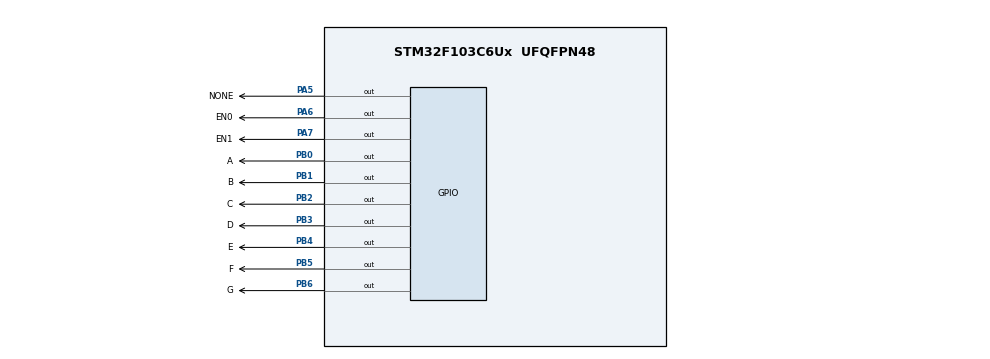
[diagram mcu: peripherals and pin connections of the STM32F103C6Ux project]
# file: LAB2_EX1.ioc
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Mcu.Family=STM32F1
Mcu.Name=STM32F103C6Ux
Mcu.Package=UFQFPN48
NVIC.PriorityGroup=NVIC_PRIORITYGROUP_4
NVIC.TIM2_IRQn=true\:0\:0\:false\:false\:true\:true\:true
PA5.GPIO_Label=NONE
PA5.Signal=GPIO_Output
PA6.GPIO_Label=EN0
PA6.Signal=GPIO_Output
PA7.GPIO_Label=EN1
PA7.Signal=GPIO_Output
PB0.GPIO_Label=A
PB0.Signal=GPIO_Output
PB1.GPIO_Label=B
PB1.Signal=GPIO_Output
PB2.GPIO_Label=C
PB2.Signal=GPIO_Output
PB3.GPIO_Label=D
PB3.Signal=GPIO_Output
PB4.GPIO_Label=E
PB4.Signal=GPIO_Output
PB5.GPIO_Label=F
PB5.Signal=GPIO_Output
PB6.GPIO_Label=G
PB6.Signal=GPIO_Output
ProjectManager.HeapSize=0x200
ProjectManager.StackSize=0x400
ProjectManager.TargetToolchain=STM32CubeIDE
RCC.APB1Freq_Value=8000000
RCC.APB2Freq_Value=8000000
TIM2.Period=9
TIM2.Prescaler=7999
VP_SYS_VS_ND.Mode=No_Debug
VP_TIM2_VS_ClockSourceINT.Mode=Internal
board=custom

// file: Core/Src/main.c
/* USER CODE BEGIN Header */
/**
  ******************************************************************************
  * @file           : main.c
  * @brief          : Main program body
  ******************************************************************************
  * @attention
  *
  * <h2><center>&copy; Copyright (c) 2025 STMicroelectronics.
  * All rights reserved.</center></h2>
  *
  * This software component is licensed by ST under BSD 3-Clause license,
  * the "License"; You may not use this file except in compliance with the
  * License. You may obtain a copy of the License at:
  *                        opensource.org/licenses/BSD-3-Clause
  *
  ******************************************************************************
  */
/* USER CODE END Header */
#include "main.h"

TIM_HandleTypeDef htim2;
int timer2_counter = 50;
int status = 0;

void SystemClock_Config(void);
static void MX_TIM2_Init(void);
static void MX_GPIO_Init(void);

/* USER CODE BEGIN 0 */

void setTimer2(int duration) {
    timer2_counter = duration;
}

void display7SEG(int num) {
    switch (num) {
        case 0:
            HAL_GPIO_WritePin(GPIOB, NUM0_Pin|NUM1_Pin|NUM2_Pin|NUM3_Pin|NUM4_Pin|NUM5_Pin, GPIO_PIN_RESET);
            HAL_GPIO_WritePin(GPIOB, NUM6_Pin, GPIO_PIN_SET);
            break;
        case 1:
            HAL_GPIO_WritePin(GPIOB, NUM0_Pin, GPIO_PIN_SET);
            HAL_GPIO_WritePin(GPIOB, NUM1_Pin|NUM2_Pin, GPIO_PIN_RESET);
            HAL_GPIO_WritePin(GPIOB, NUM3_Pin|NUM4_Pin|NUM5_Pin|NUM6_Pin, GPIO_PIN_SET);
            break;
        case 2:
            HAL_GPIO_WritePin(GPIOB, NUM0_Pin|NUM1_Pin|NUM3_Pin|NUM4_Pin|NUM6_Pin, GPIO_PIN_RESET);
            HAL_GPIO_WritePin(GPIOB, NUM2_Pin|NUM5_Pin, GPIO_PIN_SET);
            break;
        case 3:
            HAL_GPIO_WritePin(GPIOB, NUM0_Pin|NUM1_Pin|NUM2_Pin|NUM3_Pin|NUM6_Pin, GPIO_PIN_RESET);
            HAL_GPIO_WritePin(GPIOB, NUM4_Pin|NUM5_Pin, GPIO_PIN_SET);
            break;
        case 4:
            HAL_GPIO_WritePin(GPIOB, NUM1_Pin|NUM2_Pin|NUM5_Pin|NUM6_Pin, GPIO_PIN_RESET);
            HAL_GPIO_WritePin(GPIOB, NUM0_Pin|NUM3_Pin|NUM4_Pin, GPIO_PIN_SET);
            break;
        case 5:
            HAL_GPIO_WritePin(GPIOB, NUM0_Pin|NUM2_Pin|NUM3_Pin|NUM5_Pin|NUM6_Pin, GPIO_PIN_RESET);
            HAL_GPIO_WritePin(GPIOB, NUM1_Pin|NUM4_Pin, GPIO_PIN_SET);
            break;
        case 6:
            HAL_GPIO_WritePin(GPIOB, NUM0_Pin|NUM2_Pin|NUM3_Pin|NUM4_Pin|NUM5_Pin|NUM6_Pin, GPIO_PIN_RESET);
            HAL_GPIO_WritePin(GPIOB, NUM1_Pin, GPIO_PIN_SET);
            break;
        case 7:
            HAL_GPIO_WritePin(GPIOB, NUM0_Pin|NUM1_Pin|NUM2_Pin, GPIO_PIN_RESET);
            HAL_GPIO_WritePin(GPIOB, NUM3_Pin|NUM4_Pin|NUM5_Pin|NUM6_Pin, GPIO_PIN_SET);
            break;
        case 8:
            HAL_GPIO_WritePin(GPIOB, NUM0_Pin|NUM1_Pin|NUM2_Pin|NUM3_Pin|NUM4_Pin|NUM5_Pin|NUM6_Pin, GPIO_PIN_RESET);
            break;
        case 9:
            HAL_GPIO_WritePin(GPIOB, NUM0_Pin|NUM1_Pin|NUM2_Pin|NUM3_Pin|NUM5_Pin|NUM6_Pin, GPIO_PIN_RESET);
            HAL_GPIO_WritePin(GPIOB, NUM4_Pin, GPIO_PIN_SET);
            break;
        default:
            break;
    }
}
/* USER CODE END 0 */

int main(void)
{

  /* MCU Configuration--------------------------------------------------------*/

  /* Reset of all peripherals, Initializes the Flash interface and the Systick. */
  HAL_Init();

  /* Configure the system clock */
  SystemClock_Config();

  /* Initialize all configured peripherals */
  MX_TIM2_Init();
  MX_GPIO_Init();
  /* USER CODE BEGIN 2 */
  HAL_TIM_Base_Start_IT(&htim2 );
  setTimer2(50);
  /* USER CODE END 2 */

  /* Infinite loop */
  while (1)
  {

  }
}

void SystemClock_Config(void)
{
  RCC_OscInitTypeDef RCC_OscInitStruct = {0};
  RCC_ClkInitTypeDef RCC_ClkInitStruct = {0};

  /** Initializes the RCC Oscillators according to the specified parameters
  * in the RCC_OscInitTypeDef structure.
  */
  RCC_OscInitStruct.OscillatorType = RCC_OSCILLATORTYPE_HSI;
  RCC_OscInitStruct.HSIState = RCC_HSI_ON;
  RCC_OscInitStruct.HSICalibrationValue = RCC_HSICALIBRATION_DEFAULT;
  RCC_OscInitStruct.PLL.PLLState = RCC_PLL_NONE;
  if (HAL_RCC_OscConfig(&RCC_OscInitStruct) != HAL_OK)
  {
    Error_Handler();
  }
  /** Initializes the CPU, AHB and APB buses clocks
  */
  RCC_ClkInitStruct.ClockType = RCC_CLOCKTYPE_HCLK|RCC_CLOCKTYPE_SYSCLK
                              |RCC_CLOCKTYPE_PCLK1|RCC_CLOCKTYPE_PCLK2;
  RCC_ClkInitStruct.SYSCLKSource = RCC_SYSCLKSOURCE_HSI;
  RCC_ClkInitStruct.AHBCLKDivider = RCC_SYSCLK_DIV1;
  RCC_ClkInitStruct.APB1CLKDivider = RCC_HCLK_DIV1;
  RCC_ClkInitStruct.APB2CLKDivider = RCC_HCLK_DIV1;

  if (HAL_RCC_ClockConfig(&RCC_ClkInitStruct, FLASH_LATENCY_0) != HAL_OK)
  {
    Error_Handler();
  }
}

static void MX_TIM2_Init(void)
{

  TIM_ClockConfigTypeDef sClockSourceConfig = {0};
  TIM_MasterConfigTypeDef sMasterConfig = {0};

  htim2.Instance = TIM2;
  htim2.Init.Prescaler = 7999;
  htim2.Init.CounterMode = TIM_COUNTERMODE_UP;
  htim2.Init.Period = 9;
  htim2.Init.ClockDivision = TIM_CLOCKDIVISION_DIV1;
  htim2.Init.AutoReloadPreload = TIM_AUTORELOAD_PRELOAD_DISABLE;
  if (HAL_TIM_Base_Init(&htim2) != HAL_OK)
  {
    Error_Handler();
  }
  sClockSourceConfig.ClockSource = TIM_CLOCKSOURCE_INTERNAL;
  if (HAL_TIM_ConfigClockSource(&htim2, &sClockSourceConfig) != HAL_OK)
  {
    Error_Handler();
  }
  sMasterConfig.MasterOutputTrigger = TIM_TRGO_RESET;
  sMasterConfig.MasterSlaveMode = TIM_MASTERSLAVEMODE_DISABLE;
  if (HAL_TIMEx_MasterConfigSynchronization(&htim2, &sMasterConfig) != HAL_OK)
  {
    Error_Handler();
  }

}

static void MX_GPIO_Init(void)
{
  GPIO_InitTypeDef GPIO_InitStruct = {0};

  /* GPIO Ports Clock Enable */
  __HAL_RCC_GPIOA_CLK_ENABLE();
  __HAL_RCC_GPIOB_CLK_ENABLE();

  /*Configure GPIO pin Output Level */
  HAL_GPIO_WritePin(GPIOA, NONE_Pin|EN0_Pin|EN1_Pin, GPIO_PIN_RESET);

  /*Configure GPIO pin Output Level */
  HAL_GPIO_WritePin(GPIOB, NUM0_Pin|NUM1_Pin|NUM2_Pin|NUM3_Pin
                          |NUM4_Pin|NUM5_Pin|NUM6_Pin, GPIO_PIN_RESET);

  /*Configure GPIO pins : NONE_Pin EN0_Pin EN1_Pin */
  GPIO_InitStruct.Pin = NONE_Pin|EN0_Pin|EN1_Pin;
  GPIO_InitStruct.Mode = GPIO_MODE_OUTPUT_PP;
  GPIO_InitStruct.Pull = GPIO_NOPULL;
  GPIO_InitStruct.Speed = GPIO_SPEED_FREQ_LOW;
  HAL_GPIO_Init(GPIOA, &GPIO_InitStruct);

  /*Configure GPIO pins : NUM0_Pin NUM1_Pin NUM2_Pin NUM3_Pin
                           NUM4_Pin NUM5_Pin NUM6_Pin */
  GPIO_InitStruct.Pin = NUM0_Pin|NUM1_Pin|NUM2_Pin|NUM3_Pin
                          |NUM4_Pin|NUM5_Pin|NUM6_Pin;
  GPIO_InitStruct.Mode = GPIO_MODE_OUTPUT_PP;
  GPIO_InitStruct.Pull = GPIO_NOPULL;
  GPIO_InitStruct.Speed = GPIO_SPEED_FREQ_LOW;
  HAL_GPIO_Init(GPIOB, &GPIO_InitStruct);

}

/* USER CODE BEGIN 4 */
void HAL_TIM_PeriodElapsedCallback(TIM_HandleTypeDef *htim)
{
    if (htim->Instance == TIM2) {
        timer2_counter--;
        if (timer2_counter <= 0) {
            setTimer2(50); // reset về 1s
            switch (status) {
                case 0:
                    display7SEG(1);
                    HAL_GPIO_WritePin(GPIOA, EN0_Pin, GPIO_PIN_SET);
                    HAL_GPIO_WritePin(GPIOA, EN1_Pin, GPIO_PIN_RESET);
                    status = 1;
                    break;
                case 1:
                    display7SEG(2);
                    HAL_GPIO_WritePin(GPIOA, EN0_Pin, GPIO_PIN_RESET);
                    HAL_GPIO_WritePin(GPIOA, EN1_Pin, GPIO_PIN_SET);
                    status = 0;
                    break;
            }
        }
    }
}
/* USER CODE END 4 */

void Error_Handler(void)
{
  __disable_irq();
  while (1)
  {
  }
}

/************************ (C) COPYRIGHT STMicroelectronics *****END OF FILE****/
